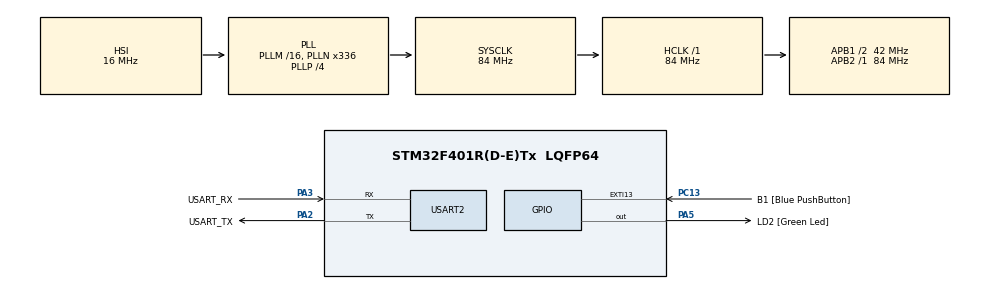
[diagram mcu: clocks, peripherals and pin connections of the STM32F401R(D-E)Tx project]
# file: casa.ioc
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Mcu.Family=STM32F4
PC15-OSC32_OUT.Mode=LSE-External-Oscillator
PA2.GPIO_PuPd=GPIO_NOPULL
RCC.CortexFreq_Value=84000000
FREERTOS.Tasks01=defaultTask,24,128,StartDefaultTask,Default,NULL,Dynamic,NULL,NULL
PC13-ANTI_TAMP.GPIO_PuPd=GPIO_NOPULL
PC13-ANTI_TAMP.GPIO_Label=B1 [Blue PushButton]
PA14.GPIO_Label=TCK
PA3.GPIO_PuPd=GPIO_NOPULL
PH1\ -\ OSC_OUT.Mode=HSE-External-Clock-Source
PA2.GPIO_Speed=GPIO_SPEED_FREQ_LOW
RCC.APB1CLKDivider=RCC_HCLK_DIV2
PC14-OSC32_IN.Signal=RCC_OSC32_IN
PA3.GPIO_Speed=GPIO_SPEED_FREQ_LOW
RCC.SYSCLKSource=RCC_SYSCLKSOURCE_PLLCLK
ProjectManager.StackSize=0x400
VP_FREERTOS_VS_CMSIS_V2.Mode=CMSIS_V2
PA13.Signal=SYS_JTMS-SWDIO
PA3.Mode=Asynchronous
PH0\ -\ OSC_IN.Mode=HSE-External-Clock-Source
PH0\ -\ OSC_IN.Signal=RCC_OSC_IN
ProjectManager.TargetToolchain=STM32CubeIDE
PA3.GPIO_Mode=GPIO_MODE_AF_PP
RCC.HCLKFreq_Value=84000000
RCC.APB2TimFreq_Value=84000000
PC15-OSC32_OUT.Signal=RCC_OSC32_OUT
RCC.AHBFreq_Value=84000000
PA5.Signal=GPIO_Output
RCC.HSE_VALUE=8000000
PH1\ -\ OSC_OUT.Signal=RCC_OSC_OUT
board=NUCLEO-F401RE
PC13-ANTI_TAMP.Signal=GPXTI13
RCC.VCOOutputFreq_Value=336000000
RCC.APB2Freq_Value=84000000
PC14-OSC32_IN.Mode=LSE-External-Oscillator
PA14.Mode=Serial_Wire
VP_SYS_VS_tim1.Mode=TIM1
PA5.GPIO_PuPd=GPIO_NOPULL
PA13.Mode=Serial_Wire
Mcu.Name=STM32F401R(D-E)Tx
PA2.Signal=USART2_TX
PA13.GPIO_Label=TMS
RCC.48MHZClocksFreq_Value=48000000
PB3.Signal=SYS_JTDO-SWO
RCC.SYSCLKFreq_VALUE=84000000
Mcu.Package=LQFP64
NVIC.TimeBase=TIM1_UP_TIM10_IRQn
PA5.GPIO_Label=LD2 [Green Led]
USART2.VirtualMode=VM_ASYNC
PC13-ANTI_TAMP.GPIO_ModeDefaultEXTI=GPIO_MODE_IT_FALLING
PA2.GPIO_Label=USART_TX
NVIC.TimeBaseIP=TIM1
PA14.Signal=SYS_JTCK-SWCLK
ProjectManager.HeapSize=0x200
NVIC.TIM1_UP_TIM10_IRQn=true\:0\:0\:false\:false\:true\:false\:false\:true
RCC.HSI_VALUE=16000000
RCC.PLLP=RCC_PLLP_DIV4
PA5.GPIO_Speed=GPIO_SPEED_FREQ_LOW
RCC.PLLQ=7
NVIC.PriorityGroup=NVIC_PRIORITYGROUP_4
RCC.PLLN=336
RCC.APB1TimFreq_Value=84000000
PA2.Mode=Asynchronous
RCC.APB1Freq_Value=42000000
PA5.GPIO_Mode=GPIO_MODE_OUTPUT_PP
PA3.GPIO_Label=USART_RX
PA3.Signal=USART2_RX
PA2.GPIO_Mode=GPIO_MODE_AF_PP
PB3.GPIO_Label=SWO

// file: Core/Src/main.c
/* USER CODE BEGIN Header */
/**
 ******************************************************************************
 * @file           : main.c
 * @brief          : Main program body
 ******************************************************************************
 * @attention
 *
 * <h2><center>&copy; Copyright (c) 2021 STMicroelectronics.
 * All rights reserved.</center></h2>
 *
 * This software component is licensed by ST under BSD 3-Clause license,
 * the "License"; You may not use this file except in compliance with the
 * License. You may obtain a copy of the License at:
 *                        opensource.org/licenses/BSD-3-Clause
 *
 ******************************************************************************
 */
/* USER CODE END Header */
#include "main.h"
#include "cmsis_os.h"

/* USER CODE BEGIN Includes */
#include "FreeRTOS.h"
#include "FreeRTOSConfig.h"
#include "keys.h"
#include "sapi.h"
#include "task.h"
#include "whackamole.h"

#include <stdio.h>
#include <string.h>
/* USER CODE END Includes */

/* USER CODE BEGIN PD */
#define RATE 1000
#define LED_RATE pdMS_TO_TICKS(RATE)

#define WELCOME_MSG  "Ejercicio D_6.\r\n"
#define USED_UART UART_USB
#define UART_RATE 115200
#define MALLOC_ERROR "Malloc Failed Hook!\n"
#define MSG_ERROR_SEM "Error al crear los semaforos.\r\n"
#define LED_ERROR LEDR
/* USER CODE END PD */
gpioMap_t leds_t[] = { LEDB, LED1, LED2, LED3 };
gpioMap_t gpio_t[] = { GPIO7, GPIO5, GPIO3, GPIO1 };

UART_HandleTypeDef huart2;

/* Definitions for defaultTask */

void SystemClock_Config(void);
static void MX_GPIO_Init(void);
static void MX_USART2_UART_Init(void);

/* USER CODE BEGIN PFP */
TickType_t keys_get_diff();
void keys_clear_diff();
void tarea_topo(void *taskParmPtr);
void tarea_principal(void *taskParmPtr);
/* USER CODE END PFP */

int main(void) {
	/* USER CODE BEGIN 1 */
	printf( WELCOME_MSG);
	/* USER CODE END 1 */

	/* MCU Configuration--------------------------------------------------------*/

	/* Reset of all peripherals, Initializes the Flash interface and the Systick. */
	HAL_Init();

	/* USER CODE BEGIN Init */
	keys_init();
	/* USER CODE END Init */

	/* Configure the system clock */
	SystemClock_Config();

	/* Initialize all configured peripherals */
	MX_GPIO_Init();
	MX_USART2_UART_Init();
	/* USER CODE BEGIN 2 */
	debugger_con_printf("\n\n\n\n", 0);
	debugger_con_printf("====== COMIENZA EL PROGRAMA ======\n\r", 0);
	/* USER CODE END 2 */

	/* Init scheduler */
	osKernelInitialize();

	/* Create the thread(s) */
	/* creation of defaultTask */

	/* USER CODE BEGIN RTOS_THREADS */
	/* add threads, ... */
	taskENTER_CRITICAL();
	printf("- se crea tarea principal \n\r");
	taskEXIT_CRITICAL();
	BaseType_t res = xTaskCreate(whackamole_service_logic, // Funcion de la tarea a ejecutar
			(const char*) "whackamole_service_logic", // Nombre de la tarea como String amigable para el usuario
			configMINIMAL_STACK_SIZE * 2, // Cantidad de stack de la tarea
			(void*) 0,                          // Parametros de tarea
			tskIDLE_PRIORITY + 1,         // Prioridad de la tarea
			0                         // Puntero a la tarea creada en el sistema
			);
	// Gestion de errores
	configASSERT(res == pdPASS);
	/* USER CODE END RTOS_THREADS */

	/* Start scheduler */

	/* We should never get here as control is now taken by the scheduler */
	/* Infinite loop */
	/* USER CODE BEGIN WHILE */
	vTaskStartScheduler();
	while (1) {
		/* USER CODE END WHILE */

	}
}

void SystemClock_Config(void) {
	RCC_OscInitTypeDef RCC_OscInitStruct = { 0 };
	RCC_ClkInitTypeDef RCC_ClkInitStruct = { 0 };

	/** Configure the main internal regulator output voltage
	 */
	__HAL_RCC_PWR_CLK_ENABLE();
	__HAL_PWR_VOLTAGESCALING_CONFIG(PWR_REGULATOR_VOLTAGE_SCALE2);
	/** Initializes the RCC Oscillators according to the specified parameters
	 * in the RCC_OscInitTypeDef structure.
	 */
	RCC_OscInitStruct.OscillatorType = RCC_OSCILLATORTYPE_HSI;
	RCC_OscInitStruct.HSIState = RCC_HSI_ON;
	RCC_OscInitStruct.HSICalibrationValue = RCC_HSICALIBRATION_DEFAULT;
	RCC_OscInitStruct.PLL.PLLState = RCC_PLL_ON;
	RCC_OscInitStruct.PLL.PLLSource = RCC_PLLSOURCE_HSI;
	RCC_OscInitStruct.PLL.PLLM = 16;
	RCC_OscInitStruct.PLL.PLLN = 336;
	RCC_OscInitStruct.PLL.PLLP = RCC_PLLP_DIV4;
	RCC_OscInitStruct.PLL.PLLQ = 7;
	if (HAL_RCC_OscConfig(&RCC_OscInitStruct) != HAL_OK) {
		Error_Handler();
	}
	/** Initializes the CPU, AHB and APB buses clocks
	 */
	RCC_ClkInitStruct.ClockType = RCC_CLOCKTYPE_HCLK | RCC_CLOCKTYPE_SYSCLK
			| RCC_CLOCKTYPE_PCLK1 | RCC_CLOCKTYPE_PCLK2;
	RCC_ClkInitStruct.SYSCLKSource = RCC_SYSCLKSOURCE_PLLCLK;
	RCC_ClkInitStruct.AHBCLKDivider = RCC_SYSCLK_DIV1;
	RCC_ClkInitStruct.APB1CLKDivider = RCC_HCLK_DIV2;
	RCC_ClkInitStruct.APB2CLKDivider = RCC_HCLK_DIV1;

	if (HAL_RCC_ClockConfig(&RCC_ClkInitStruct, FLASH_LATENCY_2) != HAL_OK) {
		Error_Handler();
	}
}

static void MX_USART2_UART_Init(void) {

	huart2.Instance = USART2;
	huart2.Init.BaudRate = 115200;
	huart2.Init.WordLength = UART_WORDLENGTH_8B;
	huart2.Init.StopBits = UART_STOPBITS_1;
	huart2.Init.Parity = UART_PARITY_NONE;
	huart2.Init.Mode = UART_MODE_TX_RX;
	huart2.Init.HwFlowCtl = UART_HWCONTROL_NONE;
	huart2.Init.OverSampling = UART_OVERSAMPLING_16;
	if (HAL_UART_Init(&huart2) != HAL_OK) {
		Error_Handler();
	}

}

static void MX_GPIO_Init(void) {
	GPIO_InitTypeDef GPIO_InitStruct = { 0 };

	/* GPIO Ports Clock Enable */
	__HAL_RCC_GPIOC_CLK_ENABLE();
	__HAL_RCC_GPIOH_CLK_ENABLE();
	__HAL_RCC_GPIOA_CLK_ENABLE();
	__HAL_RCC_GPIOB_CLK_ENABLE();

	/*Configure GPIO pin Output Level */
	HAL_GPIO_WritePin(GPIOA, GPIO_PIN_4 | GPIO_PIN_5 | GPIO_PIN_6 | GPIO_PIN_7,
			GPIO_PIN_RESET);

	/*Configure GPIO pin : B1_Pin */
	GPIO_InitStruct.Pin = B1_Pin;
	GPIO_InitStruct.Mode = GPIO_MODE_IT_FALLING;
	GPIO_InitStruct.Pull = GPIO_NOPULL;
	HAL_GPIO_Init(B1_GPIO_Port, &GPIO_InitStruct);

	/*Configure GPIO pins : PA4 PA5 PA6 PA7 */
	GPIO_InitStruct.Pin = GPIO_PIN_4 | GPIO_PIN_5 | GPIO_PIN_6 | GPIO_PIN_7;
	GPIO_InitStruct.Mode = GPIO_MODE_OUTPUT_PP;
	GPIO_InitStruct.Pull = GPIO_NOPULL;
	GPIO_InitStruct.Speed = GPIO_SPEED_FREQ_LOW;
	HAL_GPIO_Init(GPIOA, &GPIO_InitStruct);

	/*Configure GPIO pins : PA9 PA10 PA11 PA12 */
	GPIO_InitStruct.Pin = GPIO_PIN_9 | GPIO_PIN_10 | GPIO_PIN_11 | GPIO_PIN_12;
	GPIO_InitStruct.Mode = GPIO_MODE_INPUT;
	GPIO_InitStruct.Pull = GPIO_NOPULL;
	HAL_GPIO_Init(GPIOA, &GPIO_InitStruct);

}

/* USER CODE BEGIN 4 */

/* ******************************************************************************** */

/* hook que se ejecuta si al necesitar un objeto dinamico, no hay memoria disponible */
void vApplicationMallocFailedHook() {
	printf( MALLOC_ERROR);
	configASSERT(0);
}
/*==================[fin del archivo]========================================*/
int __io_putchar(int ch) {
	uint8_t c[1];
	c[0] = ch & 0x00FF;
	HAL_UART_Transmit(&huart2, &*c, 1, 10);
	return ch;
}

int _write(int file, char *ptr, int len) {
	int DataIdx;
	for (DataIdx = 0; DataIdx < len; DataIdx++) {
		__io_putchar(*ptr++);
	}
	return len;
}
/* USER CODE END 4 */

void HAL_TIM_PeriodElapsedCallback(TIM_HandleTypeDef *htim) {
	if (htim->Instance == TIM1) {
		HAL_IncTick();
	}
}

void Error_Handler(void) {
	__disable_irq();
	while (1) {
	}
}

/************************ (C) COPYRIGHT STMicroelectronics *****END OF FILE****/
